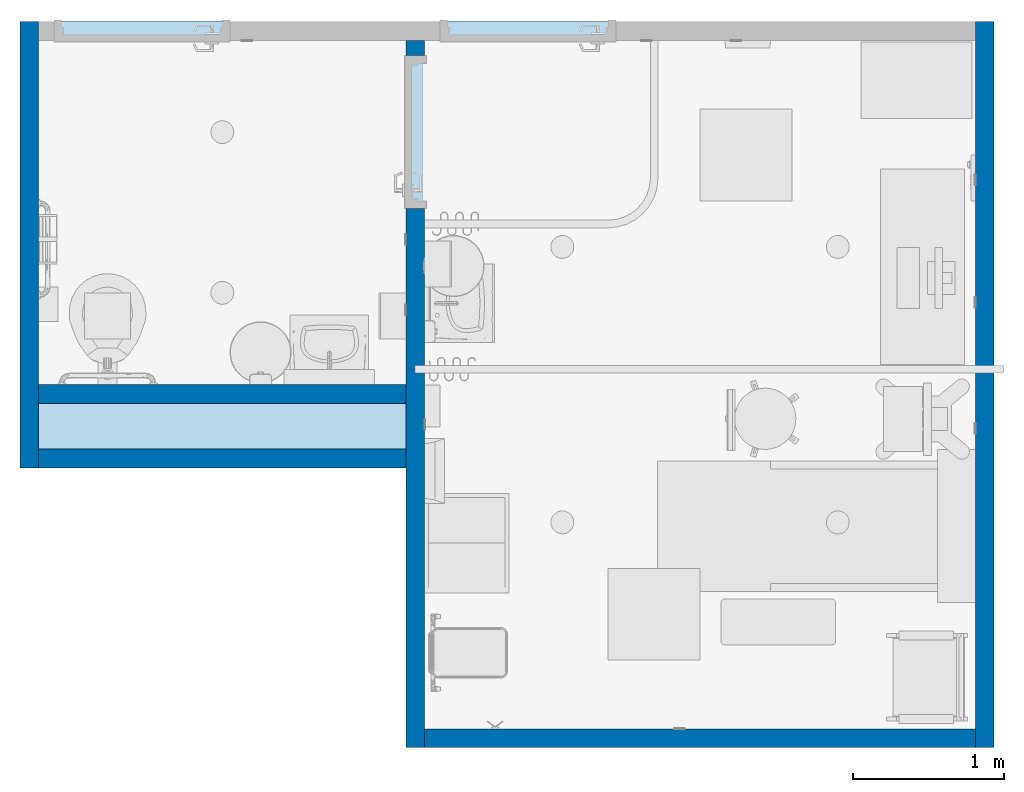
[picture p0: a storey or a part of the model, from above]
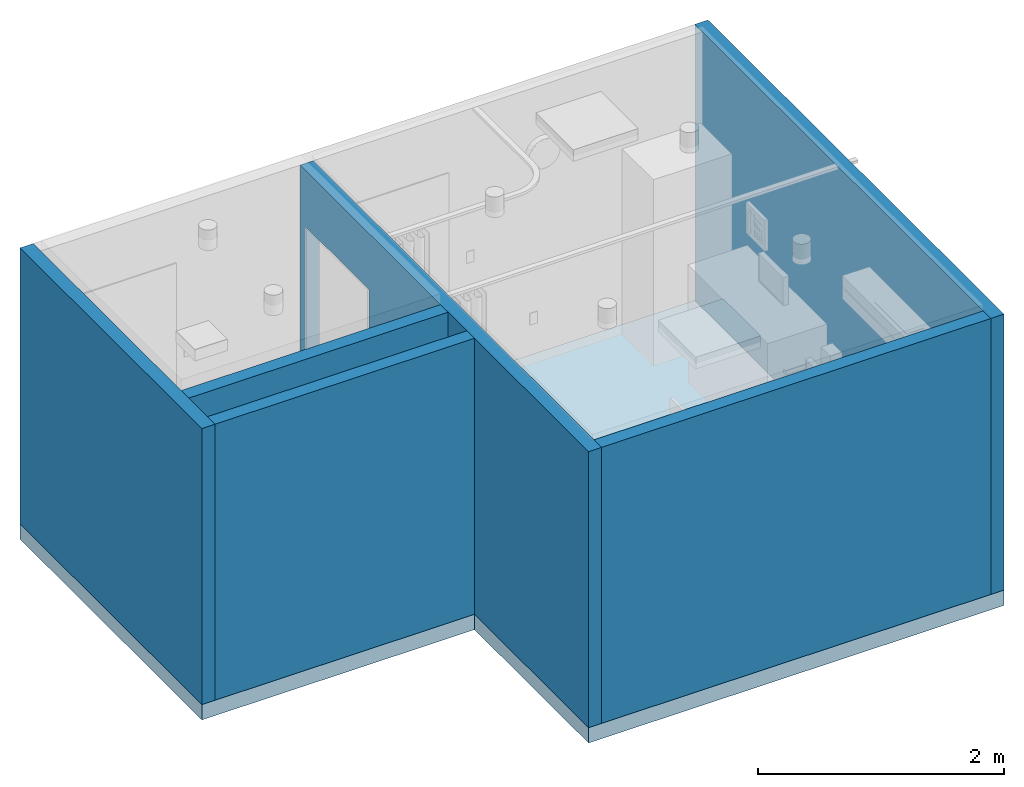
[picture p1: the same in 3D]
Properties of the parts of a building model (IFC2X3)

# File
Description: ViewDefinition [CoordinationView_V2.0]
File name: (ROOM CODE)
Time: 2018-06-28T08:55:19
Written by: The EXPRESS Data Manager Version 5.02.0100.07 : 28 Aug 2013
Made in: 20170223_1515(x64) - Exporter 18.0.0.420 - Alternate UI 18.0.0.420
Comment: STEP Physical File produced by: The EXPRESS Data Manager Version 5.02.0100.07 : 28 Aug 2013 * Module: EDMstepFileFactory/EDMstandAlone * Creation date: Thu Jun 28 08:55:19 2018 * Host: L106-OKC * Database: C:\Users\BHR~1.SPU\AppData\Local\Temp\{8DE4250A-CC08-48AF-93F4-1C9557C49E0F}\ifc * Database version: 5507 * Database creation date: Thu Jun 28 08:55:16 2018 * Schema: IFC2X3 * Model: DataRepository.ifc * Model creation date: Thu Jun 28 08:55:16 2018 * Header model: DataRepository.ifc_HeaderModel * Header model creation date: Thu Jun 28 08:55:16 2018 * EDMuser: sdai-user * EDMgroup: sdai-group * License ID and type: 5605 : Permanent license. Expiry date: * EDMstepFileFactory options: 020000

# IfcProject, (ROOM CODE)
LongName: ROOM NAME (ROOM CODE); Phase: DRAFT

# IfcSite, Default
RefLatitude: 42, 21, 31, 181945; RefLongitude: -71, -3, -24, -263305; RefElevation: 0 ft

# IfcBuilding, OUTPATIENT / PACT CLINIC (Ch. 265)
LongName: OUTPATIENT / PACT CLINIC (Ch. 265)
Pset_BuildingCommon - NumberOfStoreys: 1

# IfcBuildingStorey, DATUM
In: OUTPATIENT / PACT CLINIC (Ch. 265)
LongName: DATUM; Elevation: 0 ft

# IfcSpace (2)
In: DATUM
InteriorOrExteriorSpace: INTERNAL
Pset_SpaceCommon - Category: Rooms
Name | LongName | Reference
XDUS1 | ULTRASOUND ROOM | ULTRASOUND ROOM XDUS1
TNPG1 | TOILET, GENERAL | TOILET, GENERAL TNPG1

# IfcBuildingElementProxy: 12" x 12", Exhaust Register:12" x 12":1687395
In: TNPG1
Type - Classification: D3040100 Air Distribution Systems (Uniformat)
Pset_BuildingElementProxyCommon - Reference: 12" x 12"

# IfcBuildingElementProxy: 24" x 24", Supply Diffuser:24" x 24":1237593
In: XDUS1
Type - Classification: D3040100 Air Distribution Systems (Uniformat)
Pset_BuildingElementProxyCommon - Reference: 24" x 24"

# IfcBuildingElementProxy: 24" x 24", Return Register:24" x 24":954859
In: XDUS1
Type - Classification: D3040200 Exhaust Ventilation Systems (Uniformat)
Pset_BuildingElementProxyCommon - Reference: 24" x 24"

# IfcBuildingElementProxy: A1014 - Telephone, Wall Mounted, 1 Line, With Speaker 12"x 12", A1014 - Telephone, Wall Mounted, 1 Line, With Speaker:A1014 - Telephone, Wall Mounted, 1 Line, With Speaker 12"x 12":954864
In: XDUS1
Type - Classification: VV (Uniformat)
Pset_BuildingElementProxyCommon - Reference: A1014 - Telephone, Wall Mounted, 1 Line, With Speaker 12"x 12"

# IfcBuildingElementProxy: A1067 - Mirror, Float Glass, ADA Accessible 12"x 6", A1067 - Mirror, Float Glass, ADA Accessible:A1067 - Mirror, Float Glass, ADA Accessible 12"x 6":1547757
In: TNPG1
Type - Classification: CC (Uniformat)
Pset_BuildingElementProxyCommon - Reference: A1067 - Mirror, Float Glass, ADA Accessible 12"x 6"

# IfcBuildingElementProxy: A5075 - Dispenser, Soap, A5075 - Dispenser, Soap:A5075 - Dispenser, Soap:1547763
In: TNPG1
Classification: VV (Uniformat)
Pset_BuildingElementProxyCommon - Reference: A5075 - Dispenser, Soap

# IfcBuildingElementProxy: A5075 - Dispenser, Soap, A5075 - Dispenser, Soap:A5075 - Dispenser, Soap:954867
In: XDUS1
Type - Classification: VV (Uniformat)
Pset_BuildingElementProxyCommon - Reference: A5075 - Dispenser, Soap

# IfcBuildingElementProxy: A5082 - Dispenser, Paper Towel, Sensor, Hands Free, A5082 - Dispenser, Paper Towel, Sensor, Hands Free:A5082 - Dispenser, Paper Towel, Sensor, Hands Free:1547762
In: TNPG1
Classification: CC (Uniformat)
Pset_BuildingElementProxyCommon - Reference: A5082 - Dispenser, Paper Towel, Sensor, Hands Free

# IfcBuildingElementProxy: A5082 - Dispenser, Paper Towel, Sensor, Hands Free, A5082 - Dispenser, Paper Towel, Sensor, Hands Free:A5082 - Dispenser, Paper Towel, Sensor, Hands Free:1124743
In: XDUS1
Type - Classification: CC (Uniformat)
Pset_BuildingElementProxyCommon - Reference: A5082 - Dispenser, Paper Towel, Sensor, Hands Free

# IfcBuildingElementProxy: A5090 - Dispenser, Sanitary Napkin, SS, Surface Mounted, A5090 - Dispenser, Sanitary Napkin, SS, Surface Mounted:A5090 - Dispenser, Sanitary Napkin, SS, Surface Mounted:1547760
In: TNPG1
Classification: CC (Uniformat)
Pset_BuildingElementProxyCommon - Reference: A5090 - Dispenser, Sanitary Napkin, SS, Surface Mounted

# IfcBuildingElementProxy: A5107 - Dispenser, Glove, Surgical-Examination, Wall Mntd 10"x 4", A5107 - Dispenser, Glove, Surgical-Examination, Wall Mntd:A5107 - Dispenser, Glove, Surgical-Examination, Wall Mntd 10"x 4":954868
In: XDUS1
Type - Classification: VV (Uniformat)
Pset_BuildingElementProxyCommon - Reference: A5107 - Dispenser, Glove, Surgical-Examination, Wall Mntd 10"x 4"

# IfcBuildingElementProxy: A5108 - Waste Disposal Unit, Sharps 17"x 13", A5108 - Waste Disposal Unit, Sharps:A5108 - Waste Disposal Unit, Sharps 17"x 13":1548638
In: DATUM
Type - Classification: VV (Uniformat)
Pset_BuildingElementProxyCommon - Reference: A5108 - Waste Disposal Unit, Sharps 17"x 13"

# IfcBuildingElementProxy: A5109 - Grab Bar, 1.25 in Dia, SS, 2 Wall, W-C Accessible_Improved (2)
In: TNPG1
Type - Classification: CC (Uniformat)
Pset_BuildingElementProxyCommon - Reference: A5109 - Grab Bar, 1.25 in Dia, SS, 2 Wall, W-C Accessible_Improved
Name (A5109 - Grab Bar, 1.25 in Dia, SS, 2 Wall, W-C Accessible_Improved:A5109 - Grab Bar, 1.25 in Dia, SS, 2 Wall, W-C Accessible_Improved:...)
1547758
1547761

# IfcBuildingElementProxy: A5145 - Hook, Garment, Double, A5145 - Hook, Garment, Double:A5145 - Hook, Garment, Double:954869
In: XDUS1
Type - Classification: CC (Uniformat)
Pset_BuildingElementProxyCommon - Reference: A5145 - Hook, Garment, Double

# IfcBuildingElementProxy: A5180 - Track, Cubicle, Surface Mounted, With Curtain, Curved, A5180 - Track, Cubicle, Surface Mounted, With Curtain, Corner:A5180 - Track, Cubicle, Surface Mounted, With Curtain, Curved:1886998
In: XDUS1
Type - Classification: CC (Uniformat)
Pset_BuildingElementProxyCommon - Reference: A5180 - Track, Cubicle, Surface Mounted, With Curtain, Curved

# IfcBuildingElementProxy: A5180 - Track, Cubicle, Surface Mounted, With Curtain, Straight_12-9, Curtain 12':A5180 - Track, Cubicle, Surface Mounted, With Curtain, Straight_12-9:1886446
In: XDUS1
Type - Classification: CC (Uniformat)
Pset_BuildingElementProxyCommon - Reference: A5180 - Track, Cubicle, Surface Mounted, With Curtain, Straight_12-9

# IfcBuildingElementProxy: A5200 - Dispenser, Toilet Tissue, SS, 2-Roll, Surface Mntd, A5200 - Dispenser, Toilet Tissue, SS, 2-Roll, Surface Mntd:A5200 - Dispenser, Toilet Tissue, SS, 2-Roll, Surface Mntd:1547759
In: TNPG1
Classification: CC (Uniformat)
Pset_BuildingElementProxyCommon - Reference: A5200 - Dispenser, Toilet Tissue, SS, 2-Roll, Surface Mntd

# IfcBuildingElementProxy: Duplex (6)
Pset_BuildingElementProxyCommon - Reference: Duplex
Name (Outlet, Duplex, Wall:Duplex:...) | In
1549712 | XDUS1
1549744 | XDUS1
1549792 | XDUS1
1549850 | XDUS1
1549873 | XDUS1
1571062 | TNPG1

# IfcBuildingElementProxy: E0930 - Locker, Supply, 6 Drawers, Mobile, 29W x 20D (2), E0930 - Locker, Supply, 6 Drawers, Mobile, 29W x 20D (2):E0930 - Locker, Supply, 6 Drawers, Mobile, 29W x 20D (2):954876
In: XDUS1
Type - Classification: VV (Uniformat)
Pset_BuildingElementProxyCommon - Reference: E0930 - Locker, Supply, 6 Drawers, Mobile, 29W x 20D (2)

# IfcBuildingElementProxy: E0945 - Cart, Computer, Mobile (2), E0945 - Cart, Computer, Mobile (2):E0945 - Cart, Computer, Mobile (2):954877
In: XDUS1
Type - Classification: VV (Uniformat)
Pset_BuildingElementProxyCommon - Reference: E0945 - Cart, Computer, Mobile (2)

# IfcBuildingElementProxy: F0205 - Chair, Side With Arms, F0205 - Chair, Side With Arms:F0205 - Chair, Side With Arms:954878
In: XDUS1
Type - Classification: VV (Uniformat)
Pset_BuildingElementProxyCommon - Reference: F0205 - Chair, Side With Arms

# IfcBuildingElementProxy: F0355 - Footstool, Straight, F0355 - Footstool, Straight:F0355 - Footstool, Straight:954879
In: XDUS1
Type - Classification: VV (Uniformat)
Pset_BuildingElementProxyCommon - Reference: F0355 - Footstool, Straight

# IfcBuildingElementProxy: F2000 - Basket, Wastepaper (2)
Type - Classification: VV (Uniformat)
Pset_BuildingElementProxyCommon - Reference: F2000 - Basket, Wastepaper
Name (F2000 - Basket, Wastepaper:F2000 - Basket, Wastepaper:...) | In
954880 | XDUS1
1430753 | TNPG1

# IfcBuildingElementProxy: F3200 - Clock, Battery, 12in Dia, F3200 - Clock, Battery, 12in Dia:F3200 - Clock, Battery, 12in Dia:954881
In: XDUS1
Type - Classification: VV (Uniformat)
Pset_BuildingElementProxyCommon - Reference: F3200 - Clock, Battery, 12in Dia

# IfcBuildingElementProxy: M1801 - Computer with Flat Panel Monitor, M1801 - Computer with Flat Panel Monitor:M1801 - Computer with Flat Panel Monitor:954882
In: XDUS1
Type - Classification: VV (Uniformat)
Pset_BuildingElementProxyCommon - Reference: M1801 - Computer with Flat Panel Monitor

# IfcBuildingElementProxy: M3072 - Frame, Infectious Waste Bag with Lid, M3072 - Frame, Infectious Waste Bag with Lid1:M3072 - Frame, Infectious Waste Bag with Lid:1129868
In: XDUS1
Type - Classification: VV (Uniformat)
Pset_BuildingElementProxyCommon - Reference: M3072 - Frame, Infectious Waste Bag with Lid

# IfcBuildingElementProxy: M4655 - Stretcher, Mobile, CRS, 9 Position, M4655 - Stretcher, Mobile, CRS, 9 Position:M4655 - Stretcher, Mobile, CRS, 9 Position:954885
In: XDUS1
Type - Classification: VV (Uniformat)
Pset_BuildingElementProxyCommon - Reference: M4655 - Stretcher, Mobile, CRS, 9 Position

# IfcBuildingElementProxy: M7435 - Light, Overbed, Direct And Indirect, M7435 - Light, Overbed, Direct And Indirect:M7435 - Light, Overbed, Direct And Indirect:1552133
In: XDUS1
Pset_BuildingElementProxyCommon - Reference: M7435 - Light, Overbed, Direct And Indirect

# IfcBuildingElementProxy: M8810 - Stand, Mayo, M8810 - Stand, Mayo:M8810 - Stand, Mayo:954886
In: XDUS1
Type - Classification: VV (Uniformat)
Pset_BuildingElementProxyCommon - Reference: M8810 - Stand, Mayo

# IfcBuildingElementProxy: M8940 - Stool, Anesthesia, With Back, M8940 - Stool, Anesthesia, With Back:M8940 - Stool, Anesthesia, With Back:1313486
In: XDUS1
Type - Classification: VV (Uniformat)
Pset_BuildingElementProxyCommon - Reference: M8940 - Stool, Anesthesia, With Back

# IfcBuildingElementProxy: P3100 - Lavatory, Viteous China (2)
Type - Classification: CC (Uniformat)
Pset_BuildingElementProxyCommon - Reference: P3100 - Lavatory, Viteous China
Name (P3100 - Lavatory, Vitreous China:P3100 - Lavatory, Viteous China:...) | In
1547755 | TNPG1
1548640 | XDUS1

# IfcBuildingElementProxy: P9050 - Toilet, Wall Hung, Siphon Jet, P9050 - Toilet, Wall Hung, Siphon Jet2:P9050 - Toilet, Wall Hung, Siphon Jet:1547756
In: TNPG1
Classification: CC (Uniformat)
Pset_BuildingElementProxyCommon - Reference: P9050 - Toilet, Wall Hung, Siphon Jet

# IfcBuildingElementProxy: Single (3)
Pset_BuildingElementProxyCommon - Reference: Single
Name (Switch, Single:Single:...) | In
1570926 | XDUS1
1570981 | TNPG1
1571037 | TNPG1

# IfcBuildingElementProxy: Telephone/Data, Outlet, Communications:Telephone/Data:1549441
In: XDUS1
Pset_BuildingElementProxyCommon - Reference: Telephone/Data

# IfcBuildingElementProxy: X2100 - Scanner, Ultrasound, General Purpose, X2100 - Scanner, Ultrasound, General Purpose:X2100 - Scanner, Ultrasound, General Purpose:954888
In: XDUS1
Type - Classification: VV (Uniformat)
Pset_BuildingElementProxyCommon - Reference: X2100 - Scanner, Ultrasound, General Purpose

# IfcCovering: Compound Ceiling:2' x 2' ACT System, Compound Ceiling:2' x 2' ACT System:954838
In: DATUM
PredefinedType: CEILING; Classification: C3030210 Suspended Ceilings - Acoustical (Uniformat); Material: <Unnamed> 0.135417 ft, Acoustic Ceiling Tile 24 x 24 0.0520833 ft
Pset_CoveringCommon - Reference: 2' x 2' ACT System; Finish: Acoustic Ceiling Tile 24 x 24;; TotalThickness: 0.1875 ft

# IfcCovering: Compound Ceiling:GWB on Mtl. Stud, Compound Ceiling:GWB on Mtl. Stud:1686835
In: DATUM
PredefinedType: CEILING; Classification: C3030220 Suspended Ceilings - Gypsum Board (Uniformat); Material: <Unnamed> 0.302083 ft, gyp ceiling 0.0520833 ft
Pset_CoveringCommon - Reference: GWB on Mtl. Stud; Finish: gyp ceiling;; TotalThickness: 0.354167 ft

# IfcDoor: 36" x 84", Single - Flush:36" x 84":1508699
In: DATUM
Type - ParameterTakesPrecedence: no; Sizeable: no; Classification: C1020 Interior Doors (Uniformat)
OverallHeight: 7.16667 ft; OverallWidth: 3.33333 ft
Pset_DoorCommon - IsExternal: no; Reference: 36" x 84"

# IfcDoor: 42" x 84" (2)
In: DATUM
Type - ParameterTakesPrecedence: no; Sizeable: no; Classification: C1020 Interior Doors (Uniformat)
OverallHeight: 7.16667 ft; OverallWidth: 3.83333 ft
Pset_DoorCommon - IsExternal: no; Reference: 42" x 84"
Name (Single - Flush:42" x 84":...)
1547754
1547769

# IfcFlowTerminal: 6" (6)
Type - Classification: D5020220 Lighting - Incandescent (Uniformat)
Pset_DistributionFlowElementCommon - Reference: 6"
Name (Downlight - Recessed Can:6":...) | In
954858 | XDUS1
1131801 | XDUS1
1131990 | XDUS1
1686778 | XDUS1
1686898 | TNPG1
1686964 | TNPG1

# IfcSlab: Floor:Generic - 6", Floor:Generic - 6":954852
In: DATUM
PredefinedType: FLOOR; Classification: B1010 Floor Construction (Uniformat); Material: <Unnamed> 0.5 ft
Pset_SlabCommon - LoadBearing: no; Reference: Generic - 6"; IsExternal: no; PitchAngle: 0 deg

# IfcWallStandardCase: Basic Wall:Interior - 4 7/8" (7)
In: DATUM
Type - PredefinedType: STANDARD; Material: <Unnamed> 0.40625 ft
Classification: B2010 Exterior Walls (Uniformat)
Pset_WallCommon - Reference: Interior - 4 7/8"; LoadBearing: no; ExtendToStructure: no; IsExternal: yes
Name (Basic Wall:Interior - 4 7/8":...)
954835
954891
954892
954893
1430723
1430724
1430725
